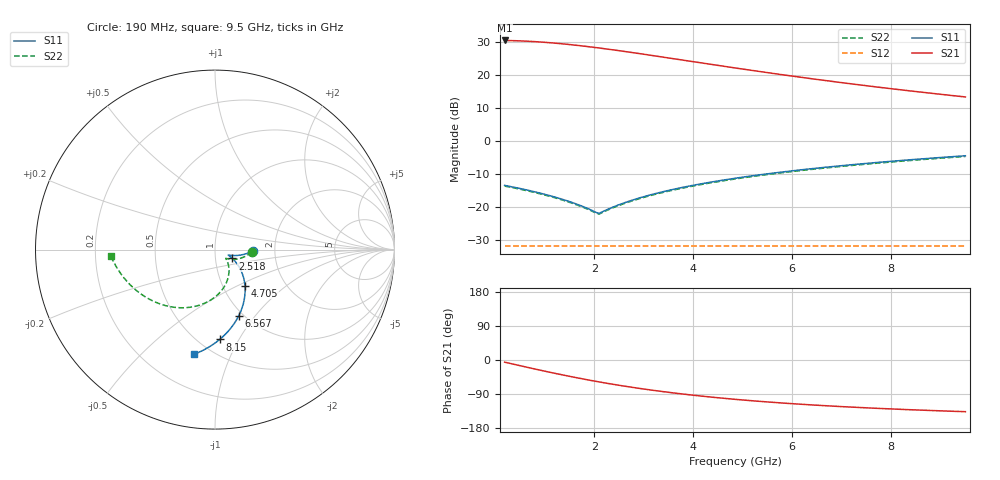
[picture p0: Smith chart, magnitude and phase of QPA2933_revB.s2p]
! written by passband
# GHZ S MA R 50
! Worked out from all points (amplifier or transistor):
!   201 points, 190 MHz to 9.5 GHz, reference 50 ohm
!   highest |S21| = 30.6 dB at 190 MHz (marker M1)
!   |S21| within 3 dB of that: start of sweep to 2.451 GHz
!   unconditionally stable (mu >= 1): 1.275 GHz to end of sweep
!   at 1.726 GHz: K = 1.04, MAG = 29.2 dB, |S12| = -32.0 dB
!   at 4.845 GHz: K = 1.54, MAG = 22.8 dB, |S12| = -32.0 dB
!   at 9.5 GHz: K = 2.22, MAG = 16.5 dB, |S12| = -32.0 dB
!   S11 on the Smith chart (normalised r, x): 190 MHz: 1.53, -0.02; 2.518 GHz: 1.21, -0.12; 4.705 GHz: 1.27, -0.55; 6.567 GHz: 0.95, -0.83; 8.15 GHz: 0.62, -0.83; 9.5 GHz: 0.41, -0.73
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0.19  0.2111 -2.0  33.8 -5.7  0.02512 -6.5  0.206 -3.5
0.3762  0.1981 -4.0  33.56 -11.3  0.02512 -12.9  0.1933 -7.0
0.5624  0.1851 -6.0  33.16 -16.8  0.02512 -19.4  0.1807 -10.4
0.79515  0.1689 -8.5  32.46 -23.6  0.02512 -27.4  0.1648 -14.8
1.0279  0.1527 -11.0  31.57 -30.3  0.02512 -35.4  0.149 -19.1
1.2141  0.1397 -13.0  30.75 -35.4  0.02512 -41.8  0.1363 -22.5
1.4003  0.1267 -15.0  29.83 -40.5  0.02512 -48.2  0.1236 -26.0
1.7727  0.1007 -18.9  27.83 -50.0  0.02512 -61.0  0.09824 -32.9
2.1451  0.08238 -22.9  25.7 -58.9  0.02512 -73.8  0.08039 -39.8
2.5175  0.1084 -26.9  23.55 -67.0  0.02512 -86.7  0.1057 -46.8
2.8899  0.1344 -30.9  21.47 -74.5  0.02512 -99.5  0.1311 -53.7
3.30885  0.1636 -35.3  19.27 -82.1  0.02512 -113.9  0.1596 -61.5
3.6347  0.1863 -38.8  17.7 -87.5  0.02512 -125.1  0.1818 -67.5
3.96055  0.2091 -42.3  16.24 -92.4  0.02512 -136.3  0.204 -73.6
4.70535  0.2611 -50.3  13.38 -102.2  0.02512 -162.0  0.2547 -87.4
4.845  0.2708 -51.7  12.91 -103.8  0.02512 -166.8  0.2642 -90.0
5.54325  0.3195 -59.2  10.83 -111.1  0.02512 169.2  0.3118 -102.9
6.4277  0.3813 -68.7  8.776 -118.8  0.02512 138.7  0.372 -119.4
6.56735  0.391 -70.1  8.499 -119.9  0.02512 133.9  0.3815 -122.0
7.96385  0.4885 -85.1  6.284 -129.0  0.02512 85.9  0.4766 -147.9
8.15005  0.5015 -87.0  6.051 -130.0  0.02512 79.5  0.4893 -151.4
9.5  0.5957 -101.5  4.674 -136.4  0.02512 33.0  0.5812 -176.4
